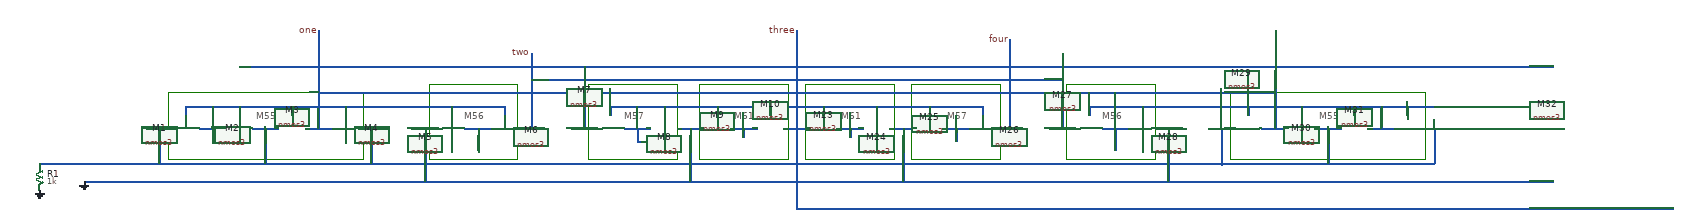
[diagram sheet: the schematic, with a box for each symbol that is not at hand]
v {xschem version=2.9.9 file_version=1.2 }
G {}
K {}
V {}
S {}
E {}
L 4 20 160 220 160 {}
L 4 220 -10 220 160 {}
L 4 20 -10 220 -10 {}
L 4 20 -10 20 160 {}
L 4 -220 160 -20 160 {}
L 4 -20 -10 -20 160 {}
L 4 -220 -10 -20 -10 {}
L 4 -220 -10 -220 160 {}
L 4 -470 160 -270 160 {}
L 4 -270 -10 -270 160 {}
L 4 -470 -10 -270 -10 {}
L 4 -470 -10 -470 160 {}
L 4 -1420 10 -1420 160 {}
L 4 -1420 160 -980 160 {}
L 4 -980 10 -980 160 {}
L 4 -1420 10 -980 10 {}
L 4 980 10 980 160 {}
L 4 980 160 1420 160 {}
L 4 1420 10 1420 160 {}
L 4 980 10 1420 10 {}
L 4 -830 160 -630 160 {}
L 4 -630 -10 -630 160 {}
L 4 -830 -10 -630 -10 {}
L 4 -830 -10 -830 160 {}
L 4 610 160 810 160 {}
L 4 810 -10 810 160 {}
L 4 610 -10 810 -10 {}
L 4 610 -10 610 160 {}
L 4 260 160 460 160 {}
L 4 460 -10 460 160 {}
L 4 260 -10 460 -10 {}
L 4 260 -10 260 160 {}
T {M55} -1220 50 0 0 0.4 0.4 {}
T {M55} 1180 50 0 0 0.4 0.4 {}
T {M56} -750 50 0 0 0.4 0.4 {}
T {M56} 690 50 0 0 0.4 0.4 {}
T {M57} 340 50 0 0 0.4 0.4 {}
T {M57} -390 50 0 0 0.4 0.4 {}
T {M61} -140 50 0 0 0.4 0.4 {}
T {M61} 100 50 0 0 0.4 0.4 {}
N -1020 40 -1020 60 { lab=one}
N -1140 40 -1140 60 { lab=one}
N -1260 40 -1260 60 { lab=one}
N -1380 40 -1380 60 { lab=one}
N -1350 90 -1290 90 { lab=one}
N -1230 90 -1170 90 { lab=#net1}
N -1110 90 -1050 90 { lab=one}
N -780 40 -780 60 { lab=one}
N -660 40 -660 60 { lab=one}
N -750 90 -690 90 { lab=#net2}
N -390 90 -330 90 { lab=#net3}
N -150 90 -90 90 { lab=#net4}
N -960 90 -960 170 { lab=#net1}
N -420 40 -420 60 { lab=three}
N -60 40 -60 60 { lab=three}
N -180 40 -180 60 { lab=three}
N -300 40 -300 60 { lab=three}
N -270 90 -210 90 { lab=GND}
N -240 90 -240 210 { lab=GND}
N -840 90 -840 210 { lab=GND}
N 0 40 0 90 { lab=three}
N -480 -50 -480 90 { lab=four}
N -1080 -130 -1080 40 { lab=one}
N -870 90 -810 90 { lab=GND}
N -990 90 -930 90 { lab=#net1}
N -630 90 -570 90 { lab=two}
N -600 -80 -600 90 { lab=two}
N -510 90 -450 90 { lab=four}
N 60 40 60 60 { lab=three}
N 180 40 180 60 { lab=three}
N 300 40 300 60 { lab=three}
N 420 40 420 60 { lab=three}
N -30 90 30 90 { lab=three}
N -420 40 420 40 { lab=three}
N 90 90 150 90 { lab=#net5}
N 210 90 270 90 { lab=GND}
N 330 90 390 90 { lab=#net6}
N 240 90 240 210 { lab=GND}
N 450 90 510 90 { lab=four}
N 570 90 630 90 { lab=two}
N 690 90 750 90 { lab=#net7}
N 810 90 870 90 { lab=GND}
N 930 90 990 90 { lab=#net1}
N 1050 90 1110 90 { lab=one}
N 1170 90 1230 90 { lab=#net1}
N 1290 90 1350 90 { lab=one}
N 1380 40 1380 60 { lab=one}
N 1020 40 1020 60 { lab=one}
N 1140 40 1140 60 { lab=one}
N 1260 40 1260 60 { lab=one}
N -1260 -50 1260 -50 { lab=four}
N 480 -50 480 90 { lab=four}
N 840 90 840 210 { lab=GND}
N 960 90 960 170 { lab=#net1}
N 600 -80 600 90 { lab=two}
N 660 40 660 60 { lab=one}
N 780 40 780 60 { lab=one}
N 660 40 1440 40 { lab=one}
N 1080 -130 1080 40 { lab=one}
N -600 -20 600 -20 { lab=two}
N -1080 10 1080 10 { lab=one}
N 0 90 0 270 { lab=three}
N -1470 90 -1410 90 { lab=#net1}
N 1410 90 1470 90 { lab=#net1}
N -1610 170 960 170 { lab=#net1}
N -1610 210 1710 210 { lab=GND}
N 0 270 1710 270 { lab=three}
N 1260 -50 1710 -50 { lab=four}
N -1200 90 -1200 160 { lab=#net1}
N -1200 160 -1200 170 { lab=#net1}
N -1080 40 -1080 90 { lab=one}
N -1320 40 -1320 90 { lab=one}
N -1440 90 -1440 170 { lab=#net1}
N -1380 40 -660 40 { lab=one}
N 960 170 1440 170 { lab=#net1}
N 1440 90 1440 170 { lab=#net1}
N 1200 90 1200 170 { lab=#net1}
N 1080 40 1080 90 { lab=one}
N 1320 40 1320 90 { lab=one}
N 1710 270 1980 270 { lab=three}
N -1650 170 -1610 170 { lab=#net1}
N -720 90 -720 140 { lab=#net2}
N 720 90 720 140 { lab=#net7}
N 360 90 360 120 { lab=#net6}
N -360 120 -350 120 { lab=#net3}
N -360 90 -360 120 { lab=#net3}
N -120 90 -120 110 { lab=#net4}
N 120 90 120 110 { lab=#net5}
N -1710 170 -1650 170 { lab=#net1}
N -0 -130 -0 40 { lab=three}
N 480 -90 480 -50 { lab=four}
N 480 -110 480 -90 { lab=four}
C {madvlsi/nmos3.sym} -1380 90 1 0 {name=M1
L=4.0
W=16
body=GND
nf=1
mult=1
ad="'int((nf+1)/2) * W/nf * 0.29'" 
pd="'2*int((nf+1)/2) * (W/nf + 0.29)'"
as="'int((nf+2)/2) * W/nf * 0.29'" 
ps="'2*int((nf+2)/2) * (W/nf + 0.29)'"
nrd="'0.29 / W'" nrs="'0.29 / W'"
sa=0 sb=0 sd=0
model=nfet_01v8
spiceprefix=X
}
C {madvlsi/nmos3.sym} -1260 90 1 0 {name=M2
L=4.0
W=16
body=GND
nf=1
mult=1
ad="'int((nf+1)/2) * W/nf * 0.29'" 
pd="'2*int((nf+1)/2) * (W/nf + 0.29)'"
as="'int((nf+2)/2) * W/nf * 0.29'" 
ps="'2*int((nf+2)/2) * (W/nf + 0.29)'"
nrd="'0.29 / W'" nrs="'0.29 / W'"
sa=0 sb=0 sd=0
model=nfet_01v8
spiceprefix=X
}
C {madvlsi/nmos3.sym} -1140 90 1 0 {name=M3
L=4.0
W=16
body=GND
nf=1
mult=1
ad="'int((nf+1)/2) * W/nf * 0.29'" 
pd="'2*int((nf+1)/2) * (W/nf + 0.29)'"
as="'int((nf+2)/2) * W/nf * 0.29'" 
ps="'2*int((nf+2)/2) * (W/nf + 0.29)'"
nrd="'0.29 / W'" nrs="'0.29 / W'"
sa=0 sb=0 sd=0
model=nfet_01v8
spiceprefix=X
}
C {madvlsi/nmos3.sym} -1020 90 1 0 {name=M4
L=4.0
W=16
body=GND
nf=1
mult=1
ad="'int((nf+1)/2) * W/nf * 0.29'" 
pd="'2*int((nf+1)/2) * (W/nf + 0.29)'"
as="'int((nf+2)/2) * W/nf * 0.29'" 
ps="'2*int((nf+2)/2) * (W/nf + 0.29)'"
nrd="'0.29 / W'" nrs="'0.29 / W'"
sa=0 sb=0 sd=0
model=nfet_01v8
spiceprefix=X
}
C {madvlsi/nmos3.sym} -780 90 1 0 {name=M5
L=4.0
W=16
body=GND
nf=1
mult=1
ad="'int((nf+1)/2) * W/nf * 0.29'" 
pd="'2*int((nf+1)/2) * (W/nf + 0.29)'"
as="'int((nf+2)/2) * W/nf * 0.29'" 
ps="'2*int((nf+2)/2) * (W/nf + 0.29)'"
nrd="'0.29 / W'" nrs="'0.29 / W'"
sa=0 sb=0 sd=0
model=nfet_01v8
spiceprefix=X
}
C {madvlsi/nmos3.sym} -660 90 1 0 {name=M6
L=4.0
W=16
body=GND
nf=1
mult=1
ad="'int((nf+1)/2) * W/nf * 0.29'" 
pd="'2*int((nf+1)/2) * (W/nf + 0.29)'"
as="'int((nf+2)/2) * W/nf * 0.29'" 
ps="'2*int((nf+2)/2) * (W/nf + 0.29)'"
nrd="'0.29 / W'" nrs="'0.29 / W'"
sa=0 sb=0 sd=0
model=nfet_01v8
spiceprefix=X
}
C {madvlsi/nmos3.sym} -420 90 1 0 {name=M7
L=4.0
W=16
body=GND
nf=1
mult=1
ad="'int((nf+1)/2) * W/nf * 0.29'" 
pd="'2*int((nf+1)/2) * (W/nf + 0.29)'"
as="'int((nf+2)/2) * W/nf * 0.29'" 
ps="'2*int((nf+2)/2) * (W/nf + 0.29)'"
nrd="'0.29 / W'" nrs="'0.29 / W'"
sa=0 sb=0 sd=0
model=nfet_01v8
spiceprefix=X
}
C {madvlsi/nmos3.sym} -300 90 1 0 {name=M8
L=4.0
W=16
body=GND
nf=1
mult=1
ad="'int((nf+1)/2) * W/nf * 0.29'" 
pd="'2*int((nf+1)/2) * (W/nf + 0.29)'"
as="'int((nf+2)/2) * W/nf * 0.29'" 
ps="'2*int((nf+2)/2) * (W/nf + 0.29)'"
nrd="'0.29 / W'" nrs="'0.29 / W'"
sa=0 sb=0 sd=0
model=nfet_01v8
spiceprefix=X
}
C {madvlsi/nmos3.sym} -180 90 1 0 {name=M9
L=4.0
W=16
body=GND
nf=1
mult=1
ad="'int((nf+1)/2) * W/nf * 0.29'" 
pd="'2*int((nf+1)/2) * (W/nf + 0.29)'"
as="'int((nf+2)/2) * W/nf * 0.29'" 
ps="'2*int((nf+2)/2) * (W/nf + 0.29)'"
nrd="'0.29 / W'" nrs="'0.29 / W'"
sa=0 sb=0 sd=0
model=nfet_01v8
spiceprefix=X
}
C {madvlsi/nmos3.sym} -60 90 1 0 {name=M10
L=4.0
W=16
body=GND
nf=1
mult=1
ad="'int((nf+1)/2) * W/nf * 0.29'" 
pd="'2*int((nf+1)/2) * (W/nf + 0.29)'"
as="'int((nf+2)/2) * W/nf * 0.29'" 
ps="'2*int((nf+2)/2) * (W/nf + 0.29)'"
nrd="'0.29 / W'" nrs="'0.29 / W'"
sa=0 sb=0 sd=0
model=nfet_01v8
spiceprefix=X
}
C {madvlsi/nmos3.sym} 60 90 1 0 {name=M23
L=4.0
W=16
body=GND
nf=1
mult=1
ad="'int((nf+1)/2) * W/nf * 0.29'" 
pd="'2*int((nf+1)/2) * (W/nf + 0.29)'"
as="'int((nf+2)/2) * W/nf * 0.29'" 
ps="'2*int((nf+2)/2) * (W/nf + 0.29)'"
nrd="'0.29 / W'" nrs="'0.29 / W'"
sa=0 sb=0 sd=0
model=nfet_01v8
spiceprefix=X
}
C {madvlsi/nmos3.sym} 180 90 1 0 {name=M24
L=4.0
W=16
body=GND
nf=1
mult=1
ad="'int((nf+1)/2) * W/nf * 0.29'" 
pd="'2*int((nf+1)/2) * (W/nf + 0.29)'"
as="'int((nf+2)/2) * W/nf * 0.29'" 
ps="'2*int((nf+2)/2) * (W/nf + 0.29)'"
nrd="'0.29 / W'" nrs="'0.29 / W'"
sa=0 sb=0 sd=0
model=nfet_01v8
spiceprefix=X
}
C {madvlsi/nmos3.sym} 300 90 1 0 {name=M25
L=4.0
W=16
body=GND
nf=1
mult=1
ad="'int((nf+1)/2) * W/nf * 0.29'" 
pd="'2*int((nf+1)/2) * (W/nf + 0.29)'"
as="'int((nf+2)/2) * W/nf * 0.29'" 
ps="'2*int((nf+2)/2) * (W/nf + 0.29)'"
nrd="'0.29 / W'" nrs="'0.29 / W'"
sa=0 sb=0 sd=0
model=nfet_01v8
spiceprefix=X
}
C {madvlsi/nmos3.sym} 420 90 1 0 {name=M26
L=4.0
W=16
body=GND
nf=1
mult=1
ad="'int((nf+1)/2) * W/nf * 0.29'" 
pd="'2*int((nf+1)/2) * (W/nf + 0.29)'"
as="'int((nf+2)/2) * W/nf * 0.29'" 
ps="'2*int((nf+2)/2) * (W/nf + 0.29)'"
nrd="'0.29 / W'" nrs="'0.29 / W'"
sa=0 sb=0 sd=0
model=nfet_01v8
spiceprefix=X
}
C {madvlsi/nmos3.sym} 660 90 1 0 {name=M27
L=4.0
W=16
body=GND
nf=1
mult=1
ad="'int((nf+1)/2) * W/nf * 0.29'" 
pd="'2*int((nf+1)/2) * (W/nf + 0.29)'"
as="'int((nf+2)/2) * W/nf * 0.29'" 
ps="'2*int((nf+2)/2) * (W/nf + 0.29)'"
nrd="'0.29 / W'" nrs="'0.29 / W'"
sa=0 sb=0 sd=0
model=nfet_01v8
spiceprefix=X
}
C {madvlsi/nmos3.sym} 780 90 1 0 {name=M28
L=4.0
W=16
body=GND
nf=1
mult=1
ad="'int((nf+1)/2) * W/nf * 0.29'" 
pd="'2*int((nf+1)/2) * (W/nf + 0.29)'"
as="'int((nf+2)/2) * W/nf * 0.29'" 
ps="'2*int((nf+2)/2) * (W/nf + 0.29)'"
nrd="'0.29 / W'" nrs="'0.29 / W'"
sa=0 sb=0 sd=0
model=nfet_01v8
spiceprefix=X
}
C {madvlsi/nmos3.sym} 1020 90 1 0 {name=M29
L=4.0
W=16
body=GND
nf=1
mult=1
ad="'int((nf+1)/2) * W/nf * 0.29'" 
pd="'2*int((nf+1)/2) * (W/nf + 0.29)'"
as="'int((nf+2)/2) * W/nf * 0.29'" 
ps="'2*int((nf+2)/2) * (W/nf + 0.29)'"
nrd="'0.29 / W'" nrs="'0.29 / W'"
sa=0 sb=0 sd=0
model=nfet_01v8
spiceprefix=X
}
C {madvlsi/nmos3.sym} 1140 90 1 0 {name=M30
L=4.0
W=16
body=GND
nf=1
mult=1
ad="'int((nf+1)/2) * W/nf * 0.29'" 
pd="'2*int((nf+1)/2) * (W/nf + 0.29)'"
as="'int((nf+2)/2) * W/nf * 0.29'" 
ps="'2*int((nf+2)/2) * (W/nf + 0.29)'"
nrd="'0.29 / W'" nrs="'0.29 / W'"
sa=0 sb=0 sd=0
model=nfet_01v8
spiceprefix=X
}
C {madvlsi/nmos3.sym} 1260 90 1 0 {name=M31
L=4.0
W=16
body=GND
nf=1
mult=1
ad="'int((nf+1)/2) * W/nf * 0.29'" 
pd="'2*int((nf+1)/2) * (W/nf + 0.29)'"
as="'int((nf+2)/2) * W/nf * 0.29'" 
ps="'2*int((nf+2)/2) * (W/nf + 0.29)'"
nrd="'0.29 / W'" nrs="'0.29 / W'"
sa=0 sb=0 sd=0
model=nfet_01v8
spiceprefix=X
}
C {madvlsi/nmos3.sym} 1380 90 1 0 {name=M32
L=4.0
W=16
body=GND
nf=1
mult=1
ad="'int((nf+1)/2) * W/nf * 0.29'" 
pd="'2*int((nf+1)/2) * (W/nf + 0.29)'"
as="'int((nf+2)/2) * W/nf * 0.29'" 
ps="'2*int((nf+2)/2) * (W/nf + 0.29)'"
nrd="'0.29 / W'" nrs="'0.29 / W'"
sa=0 sb=0 sd=0
model=nfet_01v8
spiceprefix=X
}
C {madvlsi/gnd.sym} -1610 210 1 0 {name=l5 lab=GND}
C {devices/lab_pin.sym} -1080 -130 1 0 {name=l1 sig_type=std_logic lab=one}
C {madvlsi/resistor.sym} -1710 200 0 0 {name=R1
value=1k
m=1}
C {madvlsi/gnd.sym} -1710 230 0 0 {name=l2 lab=GND}
C {devices/lab_pin.sym} -600 -80 1 0 {name=l3 sig_type=std_logic lab=two}
C {devices/lab_pin.sym} 0 -130 1 0 {name=l4 sig_type=std_logic lab=three}
C {devices/lab_pin.sym} 480 -110 1 0 {name=l6 sig_type=std_logic lab=four}
